VERSION 5.8 ;
BUSBITCHARS "[]" ;
DIVIDERCHAR "/" ;
UNITS
    DATABASE MICRONS 1000 ;
END UNITS

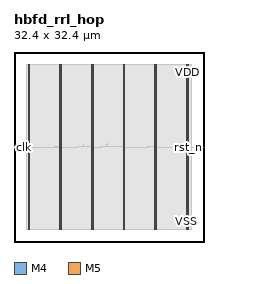
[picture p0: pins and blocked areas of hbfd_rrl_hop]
MACRO hbfd_rrl_hop
  FOREIGN hbfd_rrl_hop 0 0 ;
  CLASS BLOCK ;
  SIZE 32.4 BY 32.4 ;
  PIN clk
    DIRECTION INPUT ;
    USE SIGNAL ;
    PORT
      LAYER M4 ;
        RECT  0 16.176 0.084 16.2 ;
    END
  END clk
  PIN rst_n
    DIRECTION OUTPUT ;
    USE SIGNAL ;
    PORT
      LAYER M4 ;
        RECT  32.316 16.176 32.4 16.2 ;
    END
    PORT
      LAYER M4 ;
        RECT  30.769 16.176 32.364 16.2 ;
    END
  END rst_n
  PIN rst_n_in
    DIRECTION INPUT ;
    USE SIGNAL ;
    PORT
      LAYER M4 ;
        RECT  0 16.272 0.084 16.296 ;
    END
  END rst_n_in
  PIN VDD
    DIRECTION INOUT ;
    USE POWER ;
    PORT
      LAYER M5 ;
        RECT  29.592 2.151 29.712 30.249 ;
        RECT  24.192 2.151 24.312 30.249 ;
        RECT  18.792 2.151 18.912 30.249 ;
        RECT  13.392 2.151 13.512 30.249 ;
        RECT  7.992 2.151 8.112 30.249 ;
        RECT  2.592 2.151 2.712 30.249 ;
    END
  END VDD
  PIN VSS
    DIRECTION INOUT ;
    USE GROUND ;
    PORT
      LAYER M5 ;
        RECT  29.4 2.137 29.52 30.263 ;
        RECT  24 2.137 24.12 30.263 ;
        RECT  18.6 2.137 18.72 30.263 ;
        RECT  13.2 2.137 13.32 30.263 ;
        RECT  7.8 2.137 7.92 30.263 ;
        RECT  2.4 2.137 2.52 30.263 ;
    END
  END VSS
  # OT_OBS_CLOSED layer=M5 d_um=1.536 added=0
  OBS
    LAYER RVTN ;
     RECT  2.16 2.16 30.24 2.295 ;
     RECT  2.16 2.565 30.24 2.835 ;
     RECT  2.16 3.105 30.24 3.375 ;
     RECT  2.16 3.645 30.24 3.915 ;
     RECT  2.16 4.185 30.24 4.455 ;
     RECT  2.16 4.725 30.24 4.995 ;
     RECT  2.16 5.265 30.24 5.535 ;
     RECT  2.16 5.805 30.24 6.075 ;
     RECT  2.16 6.345 30.24 6.615 ;
     RECT  2.16 6.885 30.24 7.155 ;
     RECT  2.16 7.425 30.24 7.695 ;
     RECT  2.16 7.965 30.24 8.235 ;
     RECT  2.16 8.505 30.24 8.775 ;
     RECT  2.16 9.045 30.24 9.315 ;
     RECT  2.16 9.585 30.24 9.855 ;
     RECT  2.16 10.125 30.24 10.395 ;
     RECT  2.16 10.665 30.24 10.935 ;
     RECT  2.16 11.205 30.24 11.475 ;
     RECT  2.16 11.745 30.24 12.015 ;
     RECT  2.16 12.285 30.24 12.555 ;
     RECT  2.16 12.825 30.24 13.095 ;
     RECT  2.16 13.365 30.24 13.635 ;
     RECT  2.16 13.905 30.24 14.175 ;
     RECT  2.16 14.445 30.24 14.715 ;
     RECT  2.16 14.985 30.24 15.255 ;
     RECT  2.16 15.525 30.24 15.795 ;
     RECT  2.16 16.065 30.24 16.335 ;
     RECT  2.16 16.605 30.24 16.875 ;
     RECT  2.16 17.145 30.24 17.415 ;
     RECT  2.16 17.685 30.24 17.955 ;
     RECT  2.16 18.225 30.24 18.495 ;
     RECT  2.16 18.765 30.24 19.035 ;
     RECT  2.16 19.305 30.24 19.575 ;
     RECT  2.16 19.845 30.24 20.115 ;
     RECT  2.16 20.385 30.24 20.655 ;
     RECT  2.16 20.925 30.24 21.195 ;
     RECT  2.16 21.465 30.24 21.735 ;
     RECT  2.16 22.005 30.24 22.275 ;
     RECT  2.16 22.545 30.24 22.815 ;
     RECT  2.16 23.085 30.24 23.355 ;
     RECT  2.16 23.625 30.24 23.895 ;
     RECT  2.16 24.165 30.24 24.435 ;
     RECT  2.16 24.705 30.24 24.975 ;
     RECT  2.16 25.245 30.24 25.515 ;
     RECT  2.16 25.785 30.24 26.055 ;
     RECT  2.16 26.325 30.24 26.595 ;
     RECT  2.16 26.865 30.24 27.135 ;
     RECT  2.16 27.405 30.24 27.675 ;
     RECT  2.16 27.945 30.24 28.215 ;
     RECT  2.16 28.485 30.24 28.755 ;
     RECT  2.16 29.025 30.24 29.295 ;
     RECT  2.16 29.565 30.24 29.835 ;
     RECT  2.16 30.105 30.24 30.24 ;
    LAYER RVTP ;
     RECT  2.16 2.295 30.24 2.565 ;
     RECT  2.16 2.835 30.24 3.105 ;
     RECT  2.16 3.375 30.24 3.645 ;
     RECT  2.16 3.915 30.24 4.185 ;
     RECT  2.16 4.455 30.24 4.725 ;
     RECT  2.16 4.995 30.24 5.265 ;
     RECT  2.16 5.535 30.24 5.805 ;
     RECT  2.16 6.075 30.24 6.345 ;
     RECT  2.16 6.615 30.24 6.885 ;
     RECT  2.16 7.155 30.24 7.425 ;
     RECT  2.16 7.695 30.24 7.965 ;
     RECT  2.16 8.235 30.24 8.505 ;
     RECT  2.16 8.775 30.24 9.045 ;
     RECT  2.16 9.315 30.24 9.585 ;
     RECT  2.16 9.855 30.24 10.125 ;
     RECT  2.16 10.395 30.24 10.665 ;
     RECT  2.16 10.935 30.24 11.205 ;
     RECT  2.16 11.475 30.24 11.745 ;
     RECT  2.16 12.015 30.24 12.285 ;
     RECT  2.16 12.555 30.24 12.825 ;
     RECT  2.16 13.095 30.24 13.365 ;
     RECT  2.16 13.635 30.24 13.905 ;
     RECT  2.16 14.175 30.24 14.445 ;
     RECT  2.16 14.715 30.24 14.985 ;
     RECT  2.16 15.255 30.24 15.525 ;
     RECT  2.16 15.795 30.24 16.065 ;
     RECT  2.16 16.335 30.24 16.605 ;
     RECT  2.16 16.875 30.24 17.145 ;
     RECT  2.16 17.415 30.24 17.685 ;
     RECT  2.16 17.955 30.24 18.225 ;
     RECT  2.16 18.495 30.24 18.765 ;
     RECT  2.16 19.035 30.24 19.305 ;
     RECT  2.16 19.575 30.24 19.845 ;
     RECT  2.16 20.115 30.24 20.385 ;
     RECT  2.16 20.655 30.24 20.925 ;
     RECT  2.16 21.195 30.24 21.465 ;
     RECT  2.16 21.735 30.24 22.005 ;
     RECT  2.16 22.275 30.24 22.545 ;
     RECT  2.16 22.815 30.24 23.085 ;
     RECT  2.16 23.355 30.24 23.625 ;
     RECT  2.16 23.895 30.24 24.165 ;
     RECT  2.16 24.435 30.24 24.705 ;
     RECT  2.16 24.975 30.24 25.245 ;
     RECT  2.16 25.515 30.24 25.785 ;
     RECT  2.16 26.055 30.24 26.325 ;
     RECT  2.16 26.595 30.24 26.865 ;
     RECT  2.16 27.135 30.24 27.405 ;
     RECT  2.16 27.675 30.24 27.945 ;
     RECT  2.16 28.215 30.24 28.485 ;
     RECT  2.16 28.755 30.24 29.025 ;
     RECT  2.16 29.295 30.24 29.565 ;
     RECT  2.16 29.835 30.24 30.105 ;
    LAYER M1 ;
     RECT  2.16 2.151 30.24 30.249 ;
    LAYER M2 ;
     RECT  2.16 2.151 30.24 30.249 ;
     RECT  30.24 16.146 30.803 16.164 ;
    LAYER M3 ;
     RECT  2.415 2.143 2.505 2.413 ;
     RECT  7.815 2.143 7.905 2.413 ;
     RECT  13.215 2.143 13.305 2.413 ;
     RECT  18.615 2.143 18.705 2.413 ;
     RECT  24.015 2.143 24.105 2.413 ;
     RECT  29.415 2.143 29.505 2.413 ;
     RECT  29.415 2.413 29.697 16.105 ;
     RECT  0.108 16.075 0.126 16.205 ;
     RECT  30.78 16.141 30.798 16.205 ;
     RECT  29.415 16.105 29.898 16.259 ;
     RECT  2.415 2.413 2.697 16.267 ;
     RECT  6.84 16.171 6.858 16.301 ;
     RECT  10.836 16.171 10.854 16.301 ;
     RECT  14.832 16.171 14.85 16.301 ;
     RECT  22.824 16.171 22.842 16.301 ;
     RECT  27.756 16.171 27.774 16.411 ;
     RECT  27.756 16.411 28.494 16.501 ;
     RECT  29.415 16.259 29.754 16.501 ;
     RECT  27.756 16.501 29.754 16.529 ;
     RECT  2.415 16.267 2.862 16.565 ;
     RECT  28.296 16.529 29.697 16.565 ;
     RECT  15.732 16.501 15.75 16.601 ;
     RECT  11.916 16.501 11.934 16.673 ;
     RECT  28.296 16.565 28.314 16.799 ;
     RECT  15.948 16.681 15.966 16.835 ;
     RECT  29.124 16.565 29.697 16.835 ;
     RECT  2.415 16.565 2.697 29.987 ;
     RECT  7.815 2.413 8.097 29.987 ;
     RECT  13.215 2.413 13.497 29.987 ;
     RECT  18.615 2.413 18.897 29.987 ;
     RECT  24.015 2.413 24.297 29.987 ;
     RECT  29.415 16.835 29.697 29.987 ;
     RECT  2.415 29.987 2.505 30.257 ;
     RECT  7.815 29.987 7.905 30.257 ;
     RECT  13.215 29.987 13.305 30.257 ;
     RECT  18.615 29.987 18.705 30.257 ;
     RECT  24.015 29.987 24.105 30.257 ;
     RECT  29.415 29.987 29.505 30.257 ;
    LAYER M4 ;
     RECT  0.084 16.176 0.097 16.2 ;
     RECT  0.06 16.2 0.097 16.272 ;
     RECT  0.084 16.272 0.097 16.296 ;
     RECT  0.097 16.08 2.408 16.296 ;
     RECT  2.408 2.148 2.512 30.252 ;
     RECT  2.512 2.418 2.704 29.982 ;
     RECT  2.704 16.176 2.873 16.296 ;
     RECT  2.873 16.176 6.829 16.2 ;
     RECT  6.829 16.176 7.808 16.296 ;
     RECT  7.808 2.148 7.912 30.252 ;
     RECT  7.912 2.418 8.104 29.982 ;
     RECT  8.104 16.176 10.825 16.2 ;
     RECT  10.825 16.176 10.865 16.296 ;
     RECT  10.865 16.272 13.208 16.296 ;
     RECT  13.208 2.148 13.312 30.252 ;
     RECT  13.312 2.418 13.504 29.982 ;
     RECT  13.504 16.176 14.821 16.2 ;
     RECT  14.821 16.176 14.861 16.296 ;
     RECT  14.861 16.272 18.608 16.296 ;
     RECT  18.608 2.148 18.712 30.252 ;
     RECT  18.712 2.418 18.904 29.982 ;
     RECT  18.904 16.176 22.813 16.2 ;
     RECT  22.813 16.176 22.853 16.296 ;
     RECT  22.853 16.272 24.008 16.296 ;
     RECT  24.008 2.148 24.112 30.252 ;
     RECT  24.112 2.418 24.304 29.982 ;
     RECT  24.304 16.176 27.785 16.2 ;
     RECT  29.408 2.148 29.512 30.252 ;
     RECT  29.512 2.418 29.704 29.982 ;
    LAYER M5 ;
     RECT  2.4 2.137 2.52 2.151 ;
     RECT  7.8 2.137 7.92 2.151 ;
     RECT  13.2 2.137 13.32 2.151 ;
     RECT  18.6 2.137 18.72 2.151 ;
     RECT  24 2.137 24.12 2.151 ;
     RECT  29.4 2.137 29.52 2.151 ;
     RECT  2.4 2.151 2.712 30.249 ;
     RECT  7.8 2.151 8.112 30.249 ;
     RECT  13.2 2.151 13.512 30.249 ;
     RECT  18.6 2.151 18.912 30.249 ;
     RECT  24 2.151 24.312 30.249 ;
     RECT  29.4 2.151 29.712 30.249 ;
     RECT  2.4 30.249 2.52 30.263 ;
     RECT  7.8 30.249 7.92 30.263 ;
     RECT  13.2 30.249 13.32 30.263 ;
     RECT  18.6 30.249 18.72 30.263 ;
     RECT  24 30.249 24.12 30.263 ;
     RECT  29.4 30.249 29.52 30.263 ;
  END
END hbfd_rrl_hop
END LIBRARY
